# sar_afe_b.lef -- ADC analog front end hard macro (generated 2026-10-20)
# Generated by analog/cadence/pv/macro/export_macro.sh; do not edit.
VERSION 5.8 ;
BUSBITCHARS "[]" ;
DIVIDERCHAR "/" ;

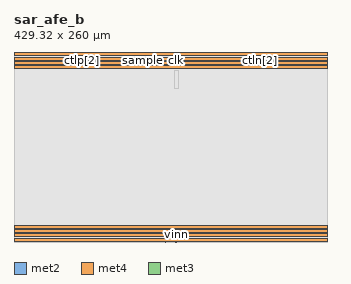
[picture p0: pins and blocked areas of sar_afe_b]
MACRO sar_afe_b
  CLASS BLOCK ;
  FOREIGN sar_afe_b 0 0 ;
  ORIGIN 0 0 ;
  SIZE 429.320 BY 260.000 ;
  SYMMETRY X Y ;
  PIN clk
    DIRECTION INPUT ;
    USE SIGNAL ;
    ANTENNAGATEAREA 1.5000 ;
    PORT
      LAYER met2 ;
        RECT 222.110 259.400 222.410 260.000 ;
    END
  END clk
  PIN ctln[0]
    DIRECTION INPUT ;
    USE SIGNAL ;
    ANTENNAGATEAREA 0.1455 ;
    PORT
      LAYER met2 ;
        RECT 327.510 259.400 327.810 260.000 ;
    END
  END ctln[0]
  PIN ctln[1]
    DIRECTION INPUT ;
    USE SIGNAL ;
    ANTENNAGATEAREA 0.1455 ;
    PORT
      LAYER met2 ;
        RECT 328.870 259.400 329.170 260.000 ;
    END
  END ctln[1]
  PIN ctln[2]
    DIRECTION INPUT ;
    USE SIGNAL ;
    ANTENNAGATEAREA 0.1455 ;
    PORT
      LAYER met2 ;
        RECT 336.350 259.400 336.650 260.000 ;
    END
  END ctln[2]
  PIN ctln[3]
    DIRECTION INPUT ;
    USE SIGNAL ;
    ANTENNAGATEAREA 0.1455 ;
    PORT
      LAYER met2 ;
        RECT 320.030 259.400 320.330 260.000 ;
    END
  END ctln[3]
  PIN ctln[4]
    DIRECTION INPUT ;
    USE SIGNAL ;
    ANTENNAGATEAREA 0.1455 ;
    PORT
      LAYER met2 ;
        RECT 353.350 259.400 353.650 260.000 ;
    END
  END ctln[4]
  PIN ctln[5]
    DIRECTION INPUT ;
    USE SIGNAL ;
    ANTENNAGATEAREA 0.1455 ;
    PORT
      LAYER met2 ;
        RECT 311.870 259.400 312.170 260.000 ;
    END
  END ctln[5]
  PIN ctln[6]
    DIRECTION INPUT ;
    USE SIGNAL ;
    ANTENNAGATEAREA 0.1455 ;
    PORT
      LAYER met2 ;
        RECT 303.030 259.400 303.330 260.000 ;
    END
  END ctln[6]
  PIN ctln[7]
    DIRECTION INPUT ;
    USE SIGNAL ;
    ANTENNAGATEAREA 0.1455 ;
    PORT
      LAYER met2 ;
        RECT 294.190 259.400 294.490 260.000 ;
    END
  END ctln[7]
  PIN ctlp[0]
    DIRECTION INPUT ;
    USE SIGNAL ;
    ANTENNAGATEAREA 0.1455 ;
    PORT
      LAYER met2 ;
        RECT 101.070 259.400 101.370 260.000 ;
    END
  END ctlp[0]
  PIN ctlp[1]
    DIRECTION INPUT ;
    USE SIGNAL ;
    ANTENNAGATEAREA 0.1455 ;
    PORT
      LAYER met2 ;
        RECT 99.710 259.400 100.010 260.000 ;
    END
  END ctlp[1]
  PIN ctlp[2]
    DIRECTION INPUT ;
    USE SIGNAL ;
    ANTENNAGATEAREA 0.1455 ;
    PORT
      LAYER met2 ;
        RECT 92.230 259.400 92.530 260.000 ;
    END
  END ctlp[2]
  PIN ctlp[3]
    DIRECTION INPUT ;
    USE SIGNAL ;
    ANTENNAGATEAREA 0.1455 ;
    PORT
      LAYER met2 ;
        RECT 109.230 259.400 109.530 260.000 ;
    END
  END ctlp[3]
  PIN ctlp[4]
    DIRECTION INPUT ;
    USE SIGNAL ;
    ANTENNAGATEAREA 0.1455 ;
    PORT
      LAYER met2 ;
        RECT 75.910 259.400 76.210 260.000 ;
    END
  END ctlp[4]
  PIN ctlp[5]
    DIRECTION INPUT ;
    USE SIGNAL ;
    ANTENNAGATEAREA 0.1455 ;
    PORT
      LAYER met2 ;
        RECT 117.390 259.400 117.690 260.000 ;
    END
  END ctlp[5]
  PIN ctlp[6]
    DIRECTION INPUT ;
    USE SIGNAL ;
    ANTENNAGATEAREA 0.1455 ;
    PORT
      LAYER met2 ;
        RECT 126.230 259.400 126.530 260.000 ;
    END
  END ctlp[6]
  PIN ctlp[7]
    DIRECTION INPUT ;
    USE SIGNAL ;
    ANTENNAGATEAREA 0.1455 ;
    PORT
      LAYER met2 ;
        RECT 135.070 259.400 135.370 260.000 ;
    END
  END ctlp[7]
  PIN outn
    DIRECTION OUTPUT ;
    USE SIGNAL ;
    ANTENNAGATEAREA 0.6000 ;
    ANTENNADIFFAREA 0.7950 ;
    PORT
      LAYER met2 ;
        RECT 211.230 259.400 211.530 260.000 ;
    END
  END outn
  PIN outp
    DIRECTION OUTPUT ;
    USE SIGNAL ;
    ANTENNAGATEAREA 0.6000 ;
    ANTENNADIFFAREA 0.7950 ;
    PORT
      LAYER met2 ;
        RECT 217.350 259.400 217.650 260.000 ;
    END
  END outp
  PIN sample
    DIRECTION INPUT ;
    USE SIGNAL ;
    ANTENNAGATEAREA 0.5110 ;
    PORT
      LAYER met2 ;
        RECT 175.870 259.400 176.170 260.000 ;
    END
  END sample
  PIN trima[0]
    DIRECTION INPUT ;
    USE SIGNAL ;
    ANTENNAGATEAREA 0.3000 ;
    PORT
      LAYER met2 ;
        RECT 192.190 259.400 192.490 260.000 ;
    END
  END trima[0]
  PIN trima[1]
    DIRECTION INPUT ;
    USE SIGNAL ;
    ANTENNAGATEAREA 0.3000 ;
    PORT
      LAYER met2 ;
        RECT 190.830 259.400 191.130 260.000 ;
    END
  END trima[1]
  PIN trima[2]
    DIRECTION INPUT ;
    USE SIGNAL ;
    ANTENNAGATEAREA 0.3000 ;
    PORT
      LAYER met2 ;
        RECT 189.470 259.400 189.770 260.000 ;
    END
  END trima[2]
  PIN trima[3]
    DIRECTION INPUT ;
    USE SIGNAL ;
    ANTENNAGATEAREA 0.3000 ;
    PORT
      LAYER met2 ;
        RECT 188.110 259.400 188.410 260.000 ;
    END
  END trima[3]
  PIN trima[4]
    DIRECTION INPUT ;
    USE SIGNAL ;
    ANTENNAGATEAREA 0.3000 ;
    PORT
      LAYER met2 ;
        RECT 186.750 259.400 187.050 260.000 ;
    END
  END trima[4]
  PIN trimb[0]
    DIRECTION INPUT ;
    USE SIGNAL ;
    ANTENNAGATEAREA 0.3000 ;
    PORT
      LAYER met2 ;
        RECT 237.070 259.400 237.370 260.000 ;
    END
  END trimb[0]
  PIN trimb[1]
    DIRECTION INPUT ;
    USE SIGNAL ;
    ANTENNAGATEAREA 0.3000 ;
    PORT
      LAYER met2 ;
        RECT 238.430 259.400 238.730 260.000 ;
    END
  END trimb[1]
  PIN trimb[2]
    DIRECTION INPUT ;
    USE SIGNAL ;
    ANTENNAGATEAREA 0.3000 ;
    PORT
      LAYER met2 ;
        RECT 239.790 259.400 240.090 260.000 ;
    END
  END trimb[2]
  PIN trimb[3]
    DIRECTION INPUT ;
    USE SIGNAL ;
    ANTENNAGATEAREA 0.3000 ;
    PORT
      LAYER met2 ;
        RECT 241.150 259.400 241.450 260.000 ;
    END
  END trimb[3]
  PIN trimb[4]
    DIRECTION INPUT ;
    USE SIGNAL ;
    ANTENNAGATEAREA 0.3000 ;
    PORT
      LAYER met2 ;
        RECT 242.510 259.400 242.810 260.000 ;
    END
  END trimb[4]
  PIN vdd
    DIRECTION INOUT ;
    USE POWER ;
    PORT
      LAYER met4 ;
        RECT 0.000 237.000 429.320 241.000 ;
    END
    PORT
      LAYER met4 ;
        RECT 0.000 19.000 429.320 23.000 ;
    END
  END vdd
  PIN vdda
    DIRECTION INOUT ;
    USE POWER ;
    PORT
      LAYER met4 ;
        RECT 0.000 249.000 429.320 253.000 ;
    END
    PORT
      LAYER met4 ;
        RECT 0.000 7.000 429.320 11.000 ;
    END
  END vdda
  PIN vinn
    DIRECTION INPUT ;
    USE SIGNAL ;
    ANTENNADIFFAREA 0.5300 ;
    PORT
      LAYER met3 ;
        RECT 221.610 0.000 222.010 0.600 ;
    END
  END vinn
  PIN vinp
    DIRECTION INPUT ;
    USE SIGNAL ;
    ANTENNADIFFAREA 0.5300 ;
    PORT
      LAYER met3 ;
        RECT 207.310 0.000 207.710 0.600 ;
    END
  END vinp
  PIN vref
    DIRECTION INOUT ;
    USE POWER ;
    PORT
      LAYER met4 ;
        RECT 0.000 243.000 429.320 247.000 ;
    END
    PORT
      LAYER met4 ;
        RECT 0.000 13.000 429.320 17.000 ;
    END
  END vref
  PIN vss
    DIRECTION INOUT ;
    USE GROUND ;
    PORT
      LAYER met4 ;
        RECT 0.000 255.000 429.320 259.000 ;
    END
    PORT
      LAYER met4 ;
        RECT 0.000 1.000 429.320 5.000 ;
    END
  END vss
  OBS
    LAYER li1 ;
      RECT 0.000 0.000 429.320 260.000 ;
    LAYER met1 ;
      RECT 0.000 0.000 429.320 260.000 ;
    LAYER met2 ;
      RECT 0.000 0.000 429.320 259.400 ;
      RECT 0.000 259.400 75.910 260.000 ;
      RECT 76.210 259.400 92.230 260.000 ;
      RECT 92.530 259.400 99.710 260.000 ;
      RECT 100.010 259.400 101.070 260.000 ;
      RECT 101.370 259.400 109.230 260.000 ;
      RECT 109.530 259.400 117.390 260.000 ;
      RECT 117.690 259.400 126.230 260.000 ;
      RECT 126.530 259.400 135.070 260.000 ;
      RECT 135.370 259.400 175.870 260.000 ;
      RECT 176.170 259.400 186.750 260.000 ;
      RECT 187.050 259.400 188.110 260.000 ;
      RECT 188.410 259.400 189.470 260.000 ;
      RECT 189.770 259.400 190.830 260.000 ;
      RECT 191.130 259.400 192.190 260.000 ;
      RECT 192.490 259.400 211.230 260.000 ;
      RECT 211.530 259.400 217.350 260.000 ;
      RECT 217.650 259.400 222.110 260.000 ;
      RECT 222.410 259.400 237.070 260.000 ;
      RECT 237.370 259.400 238.430 260.000 ;
      RECT 238.730 259.400 239.790 260.000 ;
      RECT 240.090 259.400 241.150 260.000 ;
      RECT 241.450 259.400 242.510 260.000 ;
      RECT 242.810 259.400 294.190 260.000 ;
      RECT 294.490 259.400 303.030 260.000 ;
      RECT 303.330 259.400 311.870 260.000 ;
      RECT 312.170 259.400 320.030 260.000 ;
      RECT 320.330 259.400 327.510 260.000 ;
      RECT 327.810 259.400 328.870 260.000 ;
      RECT 329.170 259.400 336.350 260.000 ;
      RECT 336.650 259.400 353.350 260.000 ;
      RECT 353.650 259.400 429.320 260.000 ;
    LAYER met3 ;
      RECT 0.000 0.000 207.310 0.600 ;
      RECT 207.710 0.000 221.610 0.600 ;
      RECT 222.010 0.000 429.320 0.600 ;
      RECT 0.000 0.600 429.320 260.000 ;
    LAYER met4 ;
      RECT 0.000 0.000 429.320 1.000 ;
      RECT 0.000 5.000 429.320 7.000 ;
      RECT 0.000 11.000 429.320 13.000 ;
      RECT 0.000 17.000 429.320 19.000 ;
      RECT 0.000 23.000 429.320 237.000 ;
      RECT 0.000 241.000 429.320 243.000 ;
      RECT 0.000 247.000 429.320 249.000 ;
      RECT 0.000 253.000 429.320 255.000 ;
      RECT 0.000 259.000 429.320 260.000 ;
    LAYER met5 ;
      RECT 219.545 210.490 225.145 234.630 ;
  END
END sar_afe_b

END LIBRARY
